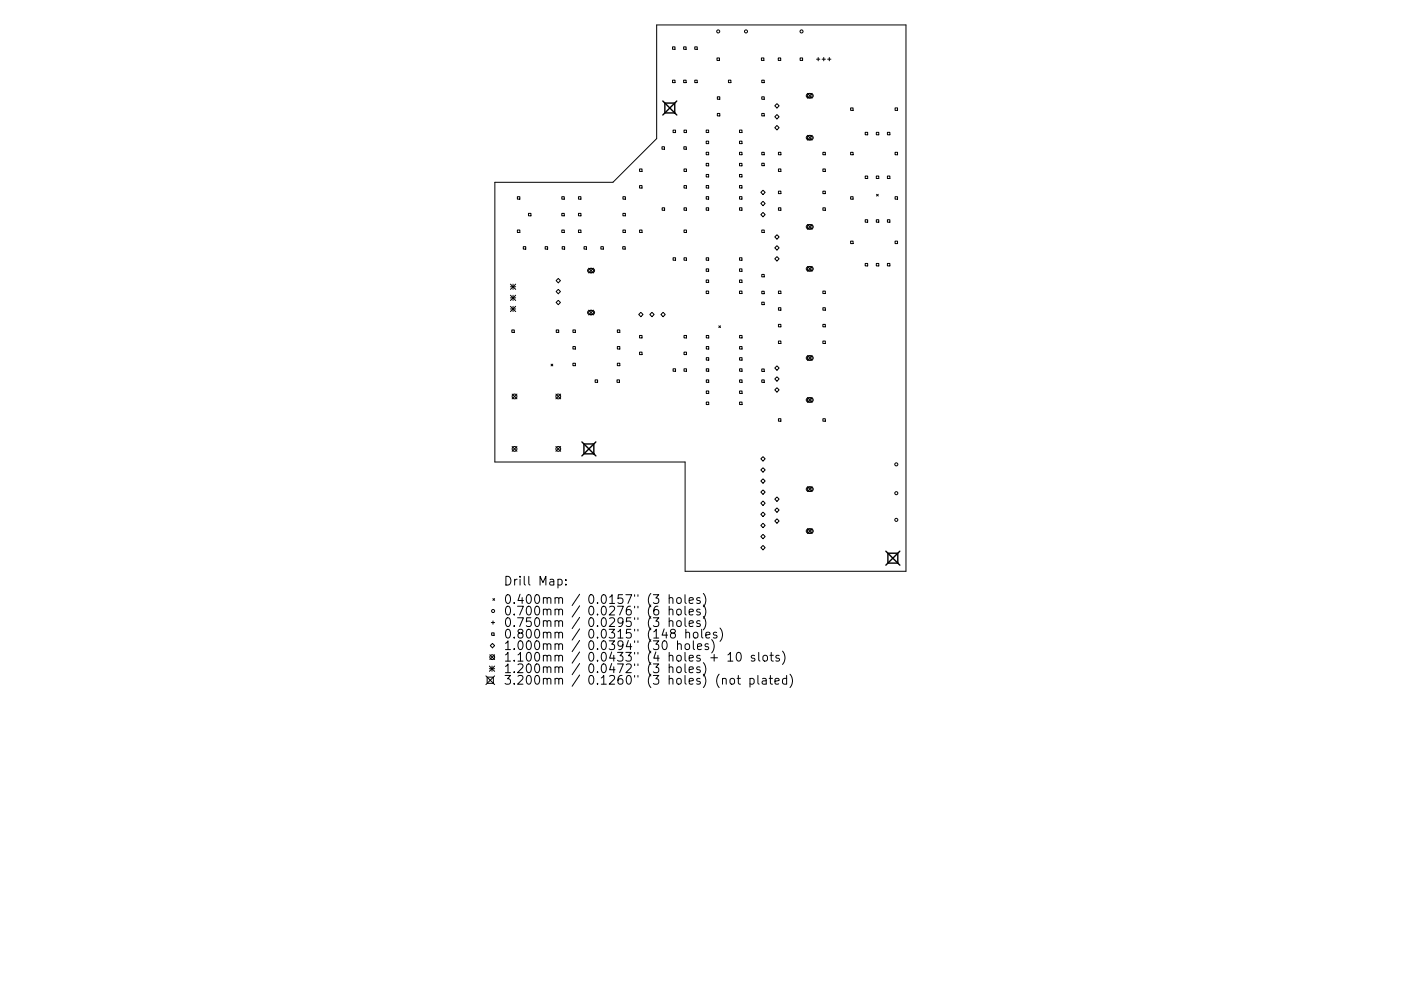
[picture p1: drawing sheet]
<svg xmlns="http://www.w3.org/2000/svg" width="297mm" height="210mm" viewBox="0 0 297 210" stroke-linecap="round" stroke-linejoin="round" font-family="sans-serif">
<defs><g id="words">
<g font-size="2.6">
<text x="106.7" y="124.2">Drill Map:</text>
<text x="106.7" y="128.1">0.400mm / 0.0157&quot; (3 holes)</text>
<text x="106.7" y="130.6">0.700mm / 0.0276&quot; (6 holes)</text>
<text x="106.7" y="133">0.750mm / 0.0295&quot; (3 holes)</text>
<text x="106.7" y="135.5">0.800mm / 0.0315&quot; (148 holes)</text>
<text x="106.7" y="137.9">1.000mm / 0.0394&quot; (30 holes)</text>
<text x="106.7" y="140.4">1.100mm / 0.0433&quot; (4 holes + 10 slots)</text>
<text x="106.7" y="142.8">1.200mm / 0.0472&quot; (3 holes)</text>
<text x="106.7" y="145.3">3.200mm / 0.1260&quot; (3 holes) (not plated)</text>
</g>
</g></defs>
<g fill="none" stroke="#000" stroke-width=".21">
<path d="M142.6 9.9h.5v.6h-.5zM142.6 17h.5v.5h-.5zM144.9 9.9h.6v.6h-.6zM144.9 17h.6v.5h-.6zM147.3 9.9h.5v.6h-.5zM147.3 17h.5v.5h-.5zM152 12.3h.5v.5h-.5zM154.4 17h.6v.5h-.6zM161.4 12.3h.6v.5h-.6zM161.5 17h.5v.5h-.5zM165 12.3h.5v.5h-.5zM169.6 12.3h.6v.5h-.6z"/>
<path d="M171.2 19.8l1 1M172.2 19.8l-1 1M173.1 12.6h.7M173.5 12.2v.7M174.3 12.6h.7M174.7 12.2v.7M175.5 12.6h.7M175.8 12.2v.7M104.9 38.7h25.1l9.2-9.3v-24.1h52.9v115.9h-46.8v-23.2h-40.4zM135.6 35.8h.5v.6h-.5zM135.6 39.4h.5v.5h-.5zM140.3 31.1h.6v.6h-.6z"/>
<path d="M142.7 27.6h.5v.5h-.5zM145 31.1h.5v.6h-.5zM145 27.6h.5v.5h-.5zM145 35.8h.5v.6h-.5zM145 39.4h.5v.5h-.5zM149.7 27.6h.5v.5h-.5zM149.7 29.9h.5v.6h-.5zM149.7 32.3h.5v.5h-.5zM149.7 34.7h.5v.5h-.5zM149.7 37h.5v.5h-.5zM149.7 39.4h.5v.5h-.5zM152.1 20.5h.5v.6h-.5z"/>
<path d="M152.1 24.1h.5v.5h-.5zM156.8 27.6h.5v.5h-.5zM156.8 29.9h.5v.6h-.5zM156.8 32.3h.5v.5h-.5zM156.8 34.7h.5v.5h-.5zM156.8 37h.5v.5h-.5zM156.8 39.4h.5v.5h-.5zM161.5 20.5h.5v.6h-.5zM161.5 24.1h.5v.5h-.5zM161.5 32.3h.5v.5h-.5zM161.5 34.6h.5v.6h-.5zM164.3 22.5l.4-.5 .5 .5-.5 .4z"/>
<path d="M164.3 24.8l.4-.5 .5 .5-.5 .4zM164.3 27.1l.4-.5 .5 .5-.5 .5zM165 32.3h.6v.5h-.6zM165 35.8h.6v.6h-.6zM171.1 20l1-.1 .3 .2v.3l-.3 .3h-.8l-.3-.3zM171.1 28.9l1-.1 .3 .2v.3l-.3 .3h-.8l-.3-.3zM171.2 28.7l1 1M172.2 28.7l-1 1M174.5 32.3h.5v.5h-.5zM174.5 35.8h.5v.6h-.5zM180.4 22.9h.5v.5h-.5zM180.4 32.3h.5v.5h-.5z"/>
<path d="M183.4 28.1h.6v.5h-.6zM183.4 37.3h.6v.6h-.6zM185.8 28.1h.5v.5h-.5zM185.8 37.3h.5v.6h-.5zM188.1 28.1h.6v.5h-.6zM188.1 37.3h.6v.6h-.6zM189.8 22.9h.5v.5h-.5zM189.8 32.3h.5v.5h-.5zM109.7 41.7h.5v.6h-.5zM109.7 48.8h.5v.5h-.5zM110.9 52.3h.6v.6h-.6zM112 45.3h.6v.5h-.6z"/>
<path d="M115.6 52.3h.5v.6h-.5zM117.9 59.5l.5-.4 .4 .4-.4 .5zM119.1 41.7h.5v.6h-.5zM119.1 45.3h.5v.5h-.5zM119.1 48.8h.5v.5h-.5zM119.2 52.3h.5v.6h-.5zM122.6 41.7h.6v.6h-.6zM122.6 45.3h.6v.5h-.6zM122.6 48.8h.6v.5h-.6zM123.8 52.3h.5v.6h-.5zM124.7 57.1l1.1-.1 .2 .2v.3l-.2 .3h-.9l-.3-.3zM124.8 56.9l1 1"/>
<path d="M125.8 56.9l-1 1M127.4 52.3h.5v.6h-.5zM132 52.3h.6v.6h-.6zM132.1 41.7h.5v.6h-.5zM132.1 45.3h.5v.5h-.5zM132.1 48.8h.5v.5h-.5zM135.6 48.8h.5v.5h-.5zM140.4 44.1h.5v.5h-.5zM142.7 54.7h.5v.5h-.5zM145 44.1h.5v.5h-.5zM145 48.8h.5v.5h-.5zM145 54.7h.5v.5h-.5z"/>
<path d="M149.7 41.7h.5v.6h-.5zM149.7 44.1h.5v.5h-.5zM149.7 54.7h.5v.5h-.5zM149.7 57h.5v.6h-.5zM149.7 59.4h.5v.5h-.5zM156.8 41.7h.5v.6h-.5zM156.8 44.1h.5v.5h-.5zM156.8 54.7h.5v.5h-.5zM156.8 57h.5v.6h-.5zM156.8 59.4h.5v.5h-.5zM161.3 40.8l.5-.4 .4 .4-.4 .5zM161.3 43.2l.5-.5 .4 .5-.4 .4z"/>
<path d="M161.3 45.5l.5-.4 .4 .4-.4 .5zM161.5 48.8h.5v.5h-.5zM161.5 58.2h.5v.5h-.5zM164.3 50.3l.4-.5 .5 .5-.5 .4zM164.3 52.6l.4-.5 .5 .5-.5 .5zM164.3 54.9l.4-.5 .5 .5-.5 .5zM165 40.6h.6v.5h-.6zM165 44.1h.6v.5h-.6zM171.1 47.8l1-.1 .3 .2v.3l-.3 .3h-.8l-.3-.3zM171.1 56.7l1-.1 .3 .2v.3l-.3 .3h-.8l-.3-.3zM171.2 47.6l1 1M171.2 56.5l1 1"/>
<path d="M172.2 47.6l-1 1M172.2 56.5l-1 1M174.5 40.6h.5v.5h-.5zM174.5 44.1h.5v.5h-.5zM180.4 41.7h.5v.6h-.5zM180.4 51.2h.5v.5h-.5zM183.4 46.6h.6v.5h-.6zM183.4 55.9h.6v.5h-.6zM185.8 46.6h.5v.5h-.5zM185.8 55.9h.5v.5h-.5zM185.8 41.2l.4 .4M186.2 41.2l-.4 .4"/>
<path d="M188.1 46.6h.6v.5h-.6zM188.1 55.9h.6v.5h-.6zM189.8 41.7h.5v.6h-.5zM189.8 51.2h.5v.5h-.5zM108.2 60.3l1.1 1.1M108.2 60.8h1.1M108.2 62.6l1.1 1.2M108.2 63.2h1.1M108.2 65l1.1 1.1M108.2 65.6h1.1M108.5 70h.5v.5h-.5zM108.8 60.3v1.1"/>
<path d="M108.8 62.6v1.2M108.8 65v1.1M109.3 60.3l-1.1 1.1M109.3 62.6l-1.1 1.2M109.3 65l-1.1 1.1M116.8 77.3l.4 .3M117.2 77.3l-.4 .3M117.9 61.9l.5-.5 .4 .5-.4 .4zM117.9 64.2l.5-.5 .4 .5-.4 .4zM117.9 70h.6v.5h-.6zM121.5 70h.5v.5h-.5zM121.5 73.5h.5v.6h-.5z"/>
<path d="M121.5 77.1h.5v.5h-.5zM124.7 66l1.1-.1 .2 .2v.3l-.2 .3h-.9l-.3-.3zM124.8 65.8l1 1M125.8 65.8l-1 1M130.9 70h.5v.5h-.5zM130.9 73.5h.5v.6h-.5zM130.9 77.1h.5v.5h-.5zM135.4 66.7l.5-.4 .4 .4-.4 .5zM135.6 71.2h.5v.5h-.5zM135.6 74.7h.5v.5h-.5zM137.8 66.7l.4-.4 .5 .4-.5 .5zM140.1 66.7l.5-.4 .5 .4-.5 .5z"/>
<path d="M142.7 78.2h.5v.6h-.5zM145 71.2h.5v.5h-.5zM145 74.7h.5v.5h-.5zM145 78.2h.5v.6h-.5zM149.7 61.8h.5v.5h-.5zM149.7 71.2h.6v.5h-.6zM149.7 73.5h.6v.6h-.6zM149.7 75.9h.6v.5h-.6zM149.7 78.2h.6v.6h-.6zM152.4 69.1l.4 .4M152.8 69.1l-.4 .4M156.8 61.8h.5v.5h-.5z"/>
<path d="M156.8 71.2h.5v.5h-.5zM156.8 73.5h.5v.6h-.5zM156.8 75.9h.5v.5h-.5zM156.8 78.2h.5v.6h-.5zM161.5 61.8h.5v.5h-.5zM161.5 64.1h.5v.5h-.5zM161.5 78.3h.5v.5h-.5zM164.3 78.1l.4-.5 .5 .5-.5 .5zM165 61.8h.6v.5h-.6zM165 65.3h.6v.5h-.6zM165 68.8h.6v.5h-.6zM165 72.4h.6v.5h-.6z"/>
<path d="M171.1 75.7l1-.1 .3 .1v.4l-.3 .3h-.8l-.3-.3zM171.2 75.4l1 1.1M172.2 75.4l-1 1.1M174.5 61.8h.5v.5h-.5zM174.5 65.3h.5v.5h-.5zM174.5 68.8h.5v.5h-.5zM174.5 72.4h.5v.5h-.5zM108.6 83.6l1 1M108.6 94.7l1 1.1M109.6 83.6l-1 1M109.6 94.7l-1 1.1M117.9 83.6l1 1"/>
<path d="M117.9 94.7l1 1.1M118.9 83.6l-1 1M118.9 94.7l-1 1.1M126.2 80.6h.5v.5h-.5zM130.8 80.6h.5v.5h-.5zM149.7 80.6h.6v.5h-.6zM149.7 83h.6v.5h-.6zM149.7 85.3h.6v.5h-.6zM156.8 80.6h.5v.5h-.5zM156.8 83h.5v.5h-.5zM156.8 85.3h.5v.5h-.5zM161.3 97.3l.5-.4 .4 .4-.4 .5z"/>
<path d="M161.5 80.6h.5v.5h-.5zM161.8 99.2l.4 .5-.4 .5-.5-.5zM164.3 80.4l.4-.5 .5 .5-.5 .5zM164.3 82.7l.4-.4 .5 .4-.5 .5zM165 88.8h.6v.6h-.6zM171.1 84.6l1-.1 .3 .1v.4l-.3 .3h-.8l-.3-.3zM171.2 84.3l1 1.1M172.2 84.3l-1 1.1M174.5 88.8h.5v.6h-.5zM161.3 106.8l.5-.5 .4 .5-.4 .4zM161.3 109.1l.5-.4 .4 .4-.4 .5zM161.8 101.6l.4 .5-.4 .4-.5-.4z"/>
<path d="M161.8 103.9l.4 .5-.4 .5-.5-.5zM161.8 111l.4 .5-.4 .4-.5-.4zM161.8 113.4l.4 .4-.4 .5-.5-.5zM161.8 115.7l.4 .5-.4 .5-.5-.5zM164.3 105.9l.4-.5 .5 .5-.5 .5zM164.3 108.2l.4-.4 .5 .4-.5 .5zM164.3 110.5l.4-.4 .5 .4-.5 .5zM171.1 103.5l1-.1 .3 .2v.3l-.3 .3h-.8l-.3-.3zM171.1 112.4l1-.1 .3 .2v.3l-.3 .3h-.8l-.3-.3zM171.2 103.3l1 1M171.2 112.2l1 1M172.2 103.3l-1 1"/>
<path d="M172.2 112.2l-1 1M103.9 138.9l1 1M103.9 137l.5-.5 .5 .5-.5 .4zM104.2 132.1h.7M104.2 134.3h.6v.5h-.6zM104.5 127l.4 .4M104.5 131.7v.7M104.9 127l-.4 .4M104.9 138.9l-1 1M118.3 123l.5-.1 .4 .3v.6l-.2 .2h-.7M120 124v.1M120 123v.2"/>
<path d="M140.6 136.1l.2-.1a1 1 0 0 1 .5 1.6l-.3 .2a1 1 0 0 1-.4-1.7zM141.9 127l.2-.2 .5 .1 .1 1.1M141.9 129.4l.2-.2 .5 .1 .1 1.2M141.9 131.9l.2-.2 .5 .1 .1 1.1M141.9 126.2v1.8M141.9 128.6v1.9M141.9 131.1v1.8M142.5 134.3l-.4-.3 .1-.3 .3-.2 .5 .1 .2 .3-.1 .2-.8 .3-.2 .3 .1 .5 .3 .2h.4l.3-.4-.1-.5-.2-.2M143.6 127l.2-.2 .6 .2v.7l-.1 .2-.5 .1-.2-.2zM143.6 129.4l.2-.2 .6 .2v.7l-.1 .3-.5 .1-.2-.2zM143.6 131.9l.2-.2 .6 .2v.7l-.1 .2-.5 .1-.2-.2zM143.6 136.8l.3-.2 .5 .1v1.1"/>
<path d="M143.6 136v1.8M145.2 126.2v1.6l.3 .2M145.2 128.6v1.6l.3 .3M145.2 131.1v1.6l.3 .2M145.3 136.8l.3-.2 .5 .2 .1 .7-.2 .2-.4 .1-.3-.2zM145.4 134.3l.3-.2 .4 .1 .1 1.2M145.4 133.5v1.9M146.1 127.4l.9-.2-.1-.3-.5-.1-.3 .3 .1 .8h.7M146.1 129.9l.9-.2-.1-.4-.5-.1-.3 .3 .1 .9h.7M146.1 132.3l.9-.2-.1-.3-.5-.1-.3 .3 .1 .8h.7M147 136v1.6l.3 .2M147.2 134.2l.4-.1 .4 .4v.5l-.4 .4-.4-.1-.2-.3v-.5z"/>
<path d="M147.9 137.2l.9-.2-.1-.3-.6-.1-.2 .2 .1 .9h.7M148.4 126.9l-.4-.1-.3 .3 .1 .2 .6 .2v.4h-.7M148.4 129.3l-.4-.1-.3 .3 .1 .3 .6 .1v.5h-.7M148.4 131.8l-.4-.1-.3 .3 .1 .2 .6 .2v.4h-.7M148.8 133.5v1.6l.2 .3M149.1 125.9a2.13 2.13 0 0 1 0 2.8M149.1 128.4a2.13 2.13 0 0 1 0 2.8M149.1 130.8a2.13 2.13 0 0 1 0 2.8M149.7 134.8l.8-.2-.1-.4-.5-.1-.2 .3v.9h.7M150.2 136.7l-.5-.1-.2 .2 .1 .3 .6 .2v.4h-.7M150.7 139.6h1.4M150.9 135.7a2.13 2.13 0 0 1 0 2.8"/>
<path d="M151.9 134.2l-.4-.1-.3 .3 .1 .3 .6 .1v.5h-.7M152.7 133.3a2.13 2.13 0 0 1 0 2.8M154.3 138.9l.6-.5v1.9M156.3 138.6l.2-.2a1 1 0 0 1 .5 1.7l-.3 .2a1 1 0 0 1-.4-1.7zM160 139.1l-.5-.1-.2 .3 .1 .3 .6 .1v.5h-.7M160.9 138.4v1.6l.2 .3M161.9 139.1l.5-.1 .3 .4v.5l-.3 .4-.5-.1-.2-.3v-.5zM163.3 139h.7M163.5 138.4v1.6l.5 .3M165.2 139.1l-.4-.1-.3 .3 .1 .3 .6 .1v.5h-.7M165.9 138.1a2.13 2.13 0 0 1 0 2.9M103 143.4l1.9 1.9"/>
<path d="M103.3 143.7h1.3v1.3h-1.3zM103.8 141.3l1.1 1.1M103.8 141.9h1.1M104.3 141.3v1.1M104.9 141.3l-1.1 1.1M104.9 143.4l-1.9 1.9M141.9 141.7l.2-.2 .5 .1 .1 1.1M141.9 140.9v1.8M143.6 141.7l.2-.2 .6 .2v.7l-.1 .2-.5 .1-.2-.2zM145.2 140.9v1.5l.3 .3M146.1 142.1l.9-.2-.1-.3-.5-.1-.3 .2 .1 .9h.7M148.4 141.6l-.4-.1-.3 .2 .1 .3 .6 .2v.4h-.7"/>
<path d="M149.1 140.6a2.13 2.13 0 0 1 0 2.8M153.2 144.1l.2-.2 .5 .1 .1 1.2M154.3 140.3h1.1M154.9 144.1l.2-.2 .6 .2v.7l-.1 .3-.5 .1-.2-.2zM156.3 143.9h.7M156.5 143.3v1.6l.1 .2 .4 .1M159 144l.5-.1 .4 .4v.5l-.2 .3h-.7M159 143.9v1.9M160.7 143.3v1.6l.3 .3M161.7 144h.7l.1 1.2M162.5 144.4l-.7 .1a.36 .36 0 0 0-.2 .3 .36 .36 0 0 0 .2 .4l.7-.1M163.1 143.9h.7"/>
<path d="M163.3 143.3v1.6l.1 .2 .4 .1M164.3 144.5l.9-.1-.1-.4-.5-.1-.3 .3 .1 .9h.7M166.8 144l-.5-.1-.4 .4v.5l.2 .3h.7M166.8 143.3v1.9M167.5 143a2.13 2.13 0 0 1 0 2.9"/>
<circle cx="152.3" cy="6.7" r=".32"/>
<circle cx="158.2" cy="6.7" r=".32"/>
<circle cx="169.9" cy="6.7" r=".32"/>
<circle cx="171.7" cy="20.3" r=".51"/>
<circle cx="171.7" cy="29.2" r=".51"/>
<circle cx="125.3" cy="57.4" r=".51"/>
<circle cx="171.7" cy="48.1" r=".51"/>
<circle cx="171.7" cy="57" r=".51"/>
<circle cx="125.3" cy="66.3" r=".51"/>
<circle cx="171.7" cy="76" r=".51"/>
<circle cx="109.1" cy="84.1" r=".51"/>
<circle cx="109.1" cy="95.2" r=".51"/>
<circle cx="118.4" cy="95.2" r=".51"/>
<circle cx="118.4" cy="84.1" r=".51"/>
<circle cx="171.7" cy="84.9" r=".51"/>
<circle cx="190" cy="98.5" r=".32"/>
<circle cx="171.7" cy="112.7" r=".51"/>
<circle cx="171.7" cy="103.8" r=".51"/>
<circle cx="190" cy="110.3" r=".32"/>
<circle cx="190" cy="104.6" r=".32"/>
<circle cx="104.4" cy="139.4" r=".51"/>
<circle cx="104.5" cy="129.6" r=".32"/>
</g>
<path d="M140.5 21.4l3 3M141 21.9h2.1v2.1h-2.1zM143.5 21.4l-3 3M123.4 93.8l2.9 2.9M123.8 94.2h2.1v2.1h-2.1zM126.3 93.8l-2.9 2.9M187.8 116.9l3 3M188.3 117.4h2.1v2.1h-2.1zM190.8 116.9l-3 3" fill="none" stroke="#000" stroke-width=".3"/>
<use href="#words"/>
</svg>
